VERSION 5.7 ;
BUSBITCHARS "[]" ;
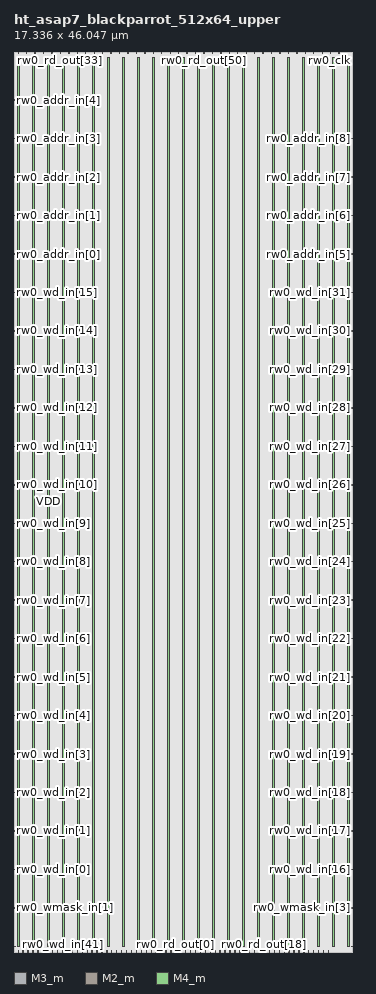
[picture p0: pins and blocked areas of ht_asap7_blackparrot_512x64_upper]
MACRO ht_asap7_blackparrot_512x64_upper
  FOREIGN ht_asap7_blackparrot_512x64_upper 0 0 ;
  SYMMETRY X Y R90 ;
  SIZE 17.336 BY 46.047 ;
  CLASS BLOCK ;
  PIN rw0_wmask_in[0]
    DIRECTION INPUT ;
    USE SIGNAL ;
    SHAPE ABUTMENT ;
    PORT
      LAYER M3_m ;
      RECT 0.000 0.276 0.072 0.300 ;
    END
  END rw0_wmask_in[0]
  PIN rw0_wmask_in[1]
    DIRECTION INPUT ;
    USE SIGNAL ;
    SHAPE ABUTMENT ;
    PORT
      LAYER M3_m ;
      RECT 0.000 2.244 0.072 2.268 ;
    END
  END rw0_wmask_in[1]
  PIN rw0_wmask_in[2]
    DIRECTION INPUT ;
    USE SIGNAL ;
    SHAPE ABUTMENT ;
    PORT
      LAYER M3_m ;
      RECT 17.264 0.276 17.336 0.300 ;
    END
  END rw0_wmask_in[2]
  PIN rw0_wmask_in[3]
    DIRECTION INPUT ;
    USE SIGNAL ;
    SHAPE ABUTMENT ;
    PORT
      LAYER M3_m ;
      RECT 17.264 2.244 17.336 2.268 ;
    END
  END rw0_wmask_in[3]
  PIN rw0_wmask_in[4]
    DIRECTION INPUT ;
    USE SIGNAL ;
    SHAPE ABUTMENT ;
    PORT
      LAYER M2_m ;
      RECT 0.207 45.993 0.225 46.047 ;
    END
  END rw0_wmask_in[4]
  PIN rw0_wmask_in[5]
    DIRECTION INPUT ;
    USE SIGNAL ;
    SHAPE ABUTMENT ;
    PORT
      LAYER M2_m ;
      RECT 0.639 45.993 0.657 46.047 ;
    END
  END rw0_wmask_in[5]
  PIN rw0_wmask_in[6]
    DIRECTION INPUT ;
    USE SIGNAL ;
    SHAPE ABUTMENT ;
    PORT
      LAYER M2_m ;
      RECT 1.071 45.993 1.089 46.047 ;
    END
  END rw0_wmask_in[6]
  PIN rw0_wmask_in[7]
    DIRECTION INPUT ;
    USE SIGNAL ;
    SHAPE ABUTMENT ;
    PORT
      LAYER M2_m ;
      RECT 1.503 45.993 1.521 46.047 ;
    END
  END rw0_wmask_in[7]
  PIN rw0_wd_in[0]
    DIRECTION INPUT ;
    USE SIGNAL ;
    SHAPE ABUTMENT ;
    PORT
      LAYER M3_m ;
      RECT 0.000 4.212 0.072 4.236 ;
    END
  END rw0_wd_in[0]
  PIN rw0_wd_in[1]
    DIRECTION INPUT ;
    USE SIGNAL ;
    SHAPE ABUTMENT ;
    PORT
      LAYER M3_m ;
      RECT 0.000 6.180 0.072 6.204 ;
    END
  END rw0_wd_in[1]
  PIN rw0_wd_in[2]
    DIRECTION INPUT ;
    USE SIGNAL ;
    SHAPE ABUTMENT ;
    PORT
      LAYER M3_m ;
      RECT 0.000 8.148 0.072 8.172 ;
    END
  END rw0_wd_in[2]
  PIN rw0_wd_in[3]
    DIRECTION INPUT ;
    USE SIGNAL ;
    SHAPE ABUTMENT ;
    PORT
      LAYER M3_m ;
      RECT 0.000 10.116 0.072 10.140 ;
    END
  END rw0_wd_in[3]
  PIN rw0_wd_in[4]
    DIRECTION INPUT ;
    USE SIGNAL ;
    SHAPE ABUTMENT ;
    PORT
      LAYER M3_m ;
      RECT 0.000 12.084 0.072 12.108 ;
    END
  END rw0_wd_in[4]
  PIN rw0_wd_in[5]
    DIRECTION INPUT ;
    USE SIGNAL ;
    SHAPE ABUTMENT ;
    PORT
      LAYER M3_m ;
      RECT 0.000 14.052 0.072 14.076 ;
    END
  END rw0_wd_in[5]
  PIN rw0_wd_in[6]
    DIRECTION INPUT ;
    USE SIGNAL ;
    SHAPE ABUTMENT ;
    PORT
      LAYER M3_m ;
      RECT 0.000 16.020 0.072 16.044 ;
    END
  END rw0_wd_in[6]
  PIN rw0_wd_in[7]
    DIRECTION INPUT ;
    USE SIGNAL ;
    SHAPE ABUTMENT ;
    PORT
      LAYER M3_m ;
      RECT 0.000 17.988 0.072 18.012 ;
    END
  END rw0_wd_in[7]
  PIN rw0_wd_in[8]
    DIRECTION INPUT ;
    USE SIGNAL ;
    SHAPE ABUTMENT ;
    PORT
      LAYER M3_m ;
      RECT 0.000 19.956 0.072 19.980 ;
    END
  END rw0_wd_in[8]
  PIN rw0_wd_in[9]
    DIRECTION INPUT ;
    USE SIGNAL ;
    SHAPE ABUTMENT ;
    PORT
      LAYER M3_m ;
      RECT 0.000 21.924 0.072 21.948 ;
    END
  END rw0_wd_in[9]
  PIN rw0_wd_in[10]
    DIRECTION INPUT ;
    USE SIGNAL ;
    SHAPE ABUTMENT ;
    PORT
      LAYER M3_m ;
      RECT 0.000 23.892 0.072 23.916 ;
    END
  END rw0_wd_in[10]
  PIN rw0_wd_in[11]
    DIRECTION INPUT ;
    USE SIGNAL ;
    SHAPE ABUTMENT ;
    PORT
      LAYER M3_m ;
      RECT 0.000 25.860 0.072 25.884 ;
    END
  END rw0_wd_in[11]
  PIN rw0_wd_in[12]
    DIRECTION INPUT ;
    USE SIGNAL ;
    SHAPE ABUTMENT ;
    PORT
      LAYER M3_m ;
      RECT 0.000 27.828 0.072 27.852 ;
    END
  END rw0_wd_in[12]
  PIN rw0_wd_in[13]
    DIRECTION INPUT ;
    USE SIGNAL ;
    SHAPE ABUTMENT ;
    PORT
      LAYER M3_m ;
      RECT 0.000 29.796 0.072 29.820 ;
    END
  END rw0_wd_in[13]
  PIN rw0_wd_in[14]
    DIRECTION INPUT ;
    USE SIGNAL ;
    SHAPE ABUTMENT ;
    PORT
      LAYER M3_m ;
      RECT 0.000 31.764 0.072 31.788 ;
    END
  END rw0_wd_in[14]
  PIN rw0_wd_in[15]
    DIRECTION INPUT ;
    USE SIGNAL ;
    SHAPE ABUTMENT ;
    PORT
      LAYER M3_m ;
      RECT 0.000 33.732 0.072 33.756 ;
    END
  END rw0_wd_in[15]
  PIN rw0_wd_in[16]
    DIRECTION INPUT ;
    USE SIGNAL ;
    SHAPE ABUTMENT ;
    PORT
      LAYER M3_m ;
      RECT 17.264 4.212 17.336 4.236 ;
    END
  END rw0_wd_in[16]
  PIN rw0_wd_in[17]
    DIRECTION INPUT ;
    USE SIGNAL ;
    SHAPE ABUTMENT ;
    PORT
      LAYER M3_m ;
      RECT 17.264 6.180 17.336 6.204 ;
    END
  END rw0_wd_in[17]
  PIN rw0_wd_in[18]
    DIRECTION INPUT ;
    USE SIGNAL ;
    SHAPE ABUTMENT ;
    PORT
      LAYER M3_m ;
      RECT 17.264 8.148 17.336 8.172 ;
    END
  END rw0_wd_in[18]
  PIN rw0_wd_in[19]
    DIRECTION INPUT ;
    USE SIGNAL ;
    SHAPE ABUTMENT ;
    PORT
      LAYER M3_m ;
      RECT 17.264 10.116 17.336 10.140 ;
    END
  END rw0_wd_in[19]
  PIN rw0_wd_in[20]
    DIRECTION INPUT ;
    USE SIGNAL ;
    SHAPE ABUTMENT ;
    PORT
      LAYER M3_m ;
      RECT 17.264 12.084 17.336 12.108 ;
    END
  END rw0_wd_in[20]
  PIN rw0_wd_in[21]
    DIRECTION INPUT ;
    USE SIGNAL ;
    SHAPE ABUTMENT ;
    PORT
      LAYER M3_m ;
      RECT 17.264 14.052 17.336 14.076 ;
    END
  END rw0_wd_in[21]
  PIN rw0_wd_in[22]
    DIRECTION INPUT ;
    USE SIGNAL ;
    SHAPE ABUTMENT ;
    PORT
      LAYER M3_m ;
      RECT 17.264 16.020 17.336 16.044 ;
    END
  END rw0_wd_in[22]
  PIN rw0_wd_in[23]
    DIRECTION INPUT ;
    USE SIGNAL ;
    SHAPE ABUTMENT ;
    PORT
      LAYER M3_m ;
      RECT 17.264 17.988 17.336 18.012 ;
    END
  END rw0_wd_in[23]
  PIN rw0_wd_in[24]
    DIRECTION INPUT ;
    USE SIGNAL ;
    SHAPE ABUTMENT ;
    PORT
      LAYER M3_m ;
      RECT 17.264 19.956 17.336 19.980 ;
    END
  END rw0_wd_in[24]
  PIN rw0_wd_in[25]
    DIRECTION INPUT ;
    USE SIGNAL ;
    SHAPE ABUTMENT ;
    PORT
      LAYER M3_m ;
      RECT 17.264 21.924 17.336 21.948 ;
    END
  END rw0_wd_in[25]
  PIN rw0_wd_in[26]
    DIRECTION INPUT ;
    USE SIGNAL ;
    SHAPE ABUTMENT ;
    PORT
      LAYER M3_m ;
      RECT 17.264 23.892 17.336 23.916 ;
    END
  END rw0_wd_in[26]
  PIN rw0_wd_in[27]
    DIRECTION INPUT ;
    USE SIGNAL ;
    SHAPE ABUTMENT ;
    PORT
      LAYER M3_m ;
      RECT 17.264 25.860 17.336 25.884 ;
    END
  END rw0_wd_in[27]
  PIN rw0_wd_in[28]
    DIRECTION INPUT ;
    USE SIGNAL ;
    SHAPE ABUTMENT ;
    PORT
      LAYER M3_m ;
      RECT 17.264 27.828 17.336 27.852 ;
    END
  END rw0_wd_in[28]
  PIN rw0_wd_in[29]
    DIRECTION INPUT ;
    USE SIGNAL ;
    SHAPE ABUTMENT ;
    PORT
      LAYER M3_m ;
      RECT 17.264 29.796 17.336 29.820 ;
    END
  END rw0_wd_in[29]
  PIN rw0_wd_in[30]
    DIRECTION INPUT ;
    USE SIGNAL ;
    SHAPE ABUTMENT ;
    PORT
      LAYER M3_m ;
      RECT 17.264 31.764 17.336 31.788 ;
    END
  END rw0_wd_in[30]
  PIN rw0_wd_in[31]
    DIRECTION INPUT ;
    USE SIGNAL ;
    SHAPE ABUTMENT ;
    PORT
      LAYER M3_m ;
      RECT 17.264 33.732 17.336 33.756 ;
    END
  END rw0_wd_in[31]
  PIN rw0_wd_in[32]
    DIRECTION INPUT ;
    USE SIGNAL ;
    SHAPE ABUTMENT ;
    PORT
      LAYER M2_m ;
      RECT 0.207 0.000 0.225 0.054 ;
    END
  END rw0_wd_in[32]
  PIN rw0_wd_in[33]
    DIRECTION INPUT ;
    USE SIGNAL ;
    SHAPE ABUTMENT ;
    PORT
      LAYER M2_m ;
      RECT 0.459 0.000 0.477 0.054 ;
    END
  END rw0_wd_in[33]
  PIN rw0_wd_in[34]
    DIRECTION INPUT ;
    USE SIGNAL ;
    SHAPE ABUTMENT ;
    PORT
      LAYER M2_m ;
      RECT 0.711 0.000 0.729 0.054 ;
    END
  END rw0_wd_in[34]
  PIN rw0_wd_in[35]
    DIRECTION INPUT ;
    USE SIGNAL ;
    SHAPE ABUTMENT ;
    PORT
      LAYER M2_m ;
      RECT 0.963 0.000 0.981 0.054 ;
    END
  END rw0_wd_in[35]
  PIN rw0_wd_in[36]
    DIRECTION INPUT ;
    USE SIGNAL ;
    SHAPE ABUTMENT ;
    PORT
      LAYER M2_m ;
      RECT 1.215 0.000 1.233 0.054 ;
    END
  END rw0_wd_in[36]
  PIN rw0_wd_in[37]
    DIRECTION INPUT ;
    USE SIGNAL ;
    SHAPE ABUTMENT ;
    PORT
      LAYER M2_m ;
      RECT 1.467 0.000 1.485 0.054 ;
    END
  END rw0_wd_in[37]
  PIN rw0_wd_in[38]
    DIRECTION INPUT ;
    USE SIGNAL ;
    SHAPE ABUTMENT ;
    PORT
      LAYER M2_m ;
      RECT 1.719 0.000 1.737 0.054 ;
    END
  END rw0_wd_in[38]
  PIN rw0_wd_in[39]
    DIRECTION INPUT ;
    USE SIGNAL ;
    SHAPE ABUTMENT ;
    PORT
      LAYER M2_m ;
      RECT 1.971 0.000 1.989 0.054 ;
    END
  END rw0_wd_in[39]
  PIN rw0_wd_in[40]
    DIRECTION INPUT ;
    USE SIGNAL ;
    SHAPE ABUTMENT ;
    PORT
      LAYER M2_m ;
      RECT 2.223 0.000 2.241 0.054 ;
    END
  END rw0_wd_in[40]
  PIN rw0_wd_in[41]
    DIRECTION INPUT ;
    USE SIGNAL ;
    SHAPE ABUTMENT ;
    PORT
      LAYER M2_m ;
      RECT 2.475 0.000 2.493 0.054 ;
    END
  END rw0_wd_in[41]
  PIN rw0_wd_in[42]
    DIRECTION INPUT ;
    USE SIGNAL ;
    SHAPE ABUTMENT ;
    PORT
      LAYER M2_m ;
      RECT 2.727 0.000 2.745 0.054 ;
    END
  END rw0_wd_in[42]
  PIN rw0_wd_in[43]
    DIRECTION INPUT ;
    USE SIGNAL ;
    SHAPE ABUTMENT ;
    PORT
      LAYER M2_m ;
      RECT 2.979 0.000 2.997 0.054 ;
    END
  END rw0_wd_in[43]
  PIN rw0_wd_in[44]
    DIRECTION INPUT ;
    USE SIGNAL ;
    SHAPE ABUTMENT ;
    PORT
      LAYER M2_m ;
      RECT 3.231 0.000 3.249 0.054 ;
    END
  END rw0_wd_in[44]
  PIN rw0_wd_in[45]
    DIRECTION INPUT ;
    USE SIGNAL ;
    SHAPE ABUTMENT ;
    PORT
      LAYER M2_m ;
      RECT 3.483 0.000 3.501 0.054 ;
    END
  END rw0_wd_in[45]
  PIN rw0_wd_in[46]
    DIRECTION INPUT ;
    USE SIGNAL ;
    SHAPE ABUTMENT ;
    PORT
      LAYER M2_m ;
      RECT 3.735 0.000 3.753 0.054 ;
    END
  END rw0_wd_in[46]
  PIN rw0_wd_in[47]
    DIRECTION INPUT ;
    USE SIGNAL ;
    SHAPE ABUTMENT ;
    PORT
      LAYER M2_m ;
      RECT 3.987 0.000 4.005 0.054 ;
    END
  END rw0_wd_in[47]
  PIN rw0_wd_in[48]
    DIRECTION INPUT ;
    USE SIGNAL ;
    SHAPE ABUTMENT ;
    PORT
      LAYER M2_m ;
      RECT 4.239 0.000 4.257 0.054 ;
    END
  END rw0_wd_in[48]
  PIN rw0_wd_in[49]
    DIRECTION INPUT ;
    USE SIGNAL ;
    SHAPE ABUTMENT ;
    PORT
      LAYER M2_m ;
      RECT 4.491 0.000 4.509 0.054 ;
    END
  END rw0_wd_in[49]
  PIN rw0_wd_in[50]
    DIRECTION INPUT ;
    USE SIGNAL ;
    SHAPE ABUTMENT ;
    PORT
      LAYER M2_m ;
      RECT 4.743 0.000 4.761 0.054 ;
    END
  END rw0_wd_in[50]
  PIN rw0_wd_in[51]
    DIRECTION INPUT ;
    USE SIGNAL ;
    SHAPE ABUTMENT ;
    PORT
      LAYER M2_m ;
      RECT 4.995 0.000 5.013 0.054 ;
    END
  END rw0_wd_in[51]
  PIN rw0_wd_in[52]
    DIRECTION INPUT ;
    USE SIGNAL ;
    SHAPE ABUTMENT ;
    PORT
      LAYER M2_m ;
      RECT 5.247 0.000 5.265 0.054 ;
    END
  END rw0_wd_in[52]
  PIN rw0_wd_in[53]
    DIRECTION INPUT ;
    USE SIGNAL ;
    SHAPE ABUTMENT ;
    PORT
      LAYER M2_m ;
      RECT 5.499 0.000 5.517 0.054 ;
    END
  END rw0_wd_in[53]
  PIN rw0_wd_in[54]
    DIRECTION INPUT ;
    USE SIGNAL ;
    SHAPE ABUTMENT ;
    PORT
      LAYER M2_m ;
      RECT 5.751 0.000 5.769 0.054 ;
    END
  END rw0_wd_in[54]
  PIN rw0_wd_in[55]
    DIRECTION INPUT ;
    USE SIGNAL ;
    SHAPE ABUTMENT ;
    PORT
      LAYER M2_m ;
      RECT 6.003 0.000 6.021 0.054 ;
    END
  END rw0_wd_in[55]
  PIN rw0_wd_in[56]
    DIRECTION INPUT ;
    USE SIGNAL ;
    SHAPE ABUTMENT ;
    PORT
      LAYER M2_m ;
      RECT 6.255 0.000 6.273 0.054 ;
    END
  END rw0_wd_in[56]
  PIN rw0_wd_in[57]
    DIRECTION INPUT ;
    USE SIGNAL ;
    SHAPE ABUTMENT ;
    PORT
      LAYER M2_m ;
      RECT 6.507 0.000 6.525 0.054 ;
    END
  END rw0_wd_in[57]
  PIN rw0_wd_in[58]
    DIRECTION INPUT ;
    USE SIGNAL ;
    SHAPE ABUTMENT ;
    PORT
      LAYER M2_m ;
      RECT 6.759 0.000 6.777 0.054 ;
    END
  END rw0_wd_in[58]
  PIN rw0_wd_in[59]
    DIRECTION INPUT ;
    USE SIGNAL ;
    SHAPE ABUTMENT ;
    PORT
      LAYER M2_m ;
      RECT 7.011 0.000 7.029 0.054 ;
    END
  END rw0_wd_in[59]
  PIN rw0_wd_in[60]
    DIRECTION INPUT ;
    USE SIGNAL ;
    SHAPE ABUTMENT ;
    PORT
      LAYER M2_m ;
      RECT 7.263 0.000 7.281 0.054 ;
    END
  END rw0_wd_in[60]
  PIN rw0_wd_in[61]
    DIRECTION INPUT ;
    USE SIGNAL ;
    SHAPE ABUTMENT ;
    PORT
      LAYER M2_m ;
      RECT 7.515 0.000 7.533 0.054 ;
    END
  END rw0_wd_in[61]
  PIN rw0_wd_in[62]
    DIRECTION INPUT ;
    USE SIGNAL ;
    SHAPE ABUTMENT ;
    PORT
      LAYER M2_m ;
      RECT 7.767 0.000 7.785 0.054 ;
    END
  END rw0_wd_in[62]
  PIN rw0_wd_in[63]
    DIRECTION INPUT ;
    USE SIGNAL ;
    SHAPE ABUTMENT ;
    PORT
      LAYER M2_m ;
      RECT 8.019 0.000 8.037 0.054 ;
    END
  END rw0_wd_in[63]
  PIN rw0_rd_out[0]
    DIRECTION OUTPUT ;
    USE SIGNAL ;
    SHAPE ABUTMENT ;
    PORT
      LAYER M2_m ;
      RECT 8.271 0.000 8.289 0.054 ;
    END
  END rw0_rd_out[0]
  PIN rw0_rd_out[1]
    DIRECTION OUTPUT ;
    USE SIGNAL ;
    SHAPE ABUTMENT ;
    PORT
      LAYER M2_m ;
      RECT 8.523 0.000 8.541 0.054 ;
    END
  END rw0_rd_out[1]
  PIN rw0_rd_out[2]
    DIRECTION OUTPUT ;
    USE SIGNAL ;
    SHAPE ABUTMENT ;
    PORT
      LAYER M2_m ;
      RECT 8.775 0.000 8.793 0.054 ;
    END
  END rw0_rd_out[2]
  PIN rw0_rd_out[3]
    DIRECTION OUTPUT ;
    USE SIGNAL ;
    SHAPE ABUTMENT ;
    PORT
      LAYER M2_m ;
      RECT 9.027 0.000 9.045 0.054 ;
    END
  END rw0_rd_out[3]
  PIN rw0_rd_out[4]
    DIRECTION OUTPUT ;
    USE SIGNAL ;
    SHAPE ABUTMENT ;
    PORT
      LAYER M2_m ;
      RECT 9.279 0.000 9.297 0.054 ;
    END
  END rw0_rd_out[4]
  PIN rw0_rd_out[5]
    DIRECTION OUTPUT ;
    USE SIGNAL ;
    SHAPE ABUTMENT ;
    PORT
      LAYER M2_m ;
      RECT 9.531 0.000 9.549 0.054 ;
    END
  END rw0_rd_out[5]
  PIN rw0_rd_out[6]
    DIRECTION OUTPUT ;
    USE SIGNAL ;
    SHAPE ABUTMENT ;
    PORT
      LAYER M2_m ;
      RECT 9.783 0.000 9.801 0.054 ;
    END
  END rw0_rd_out[6]
  PIN rw0_rd_out[7]
    DIRECTION OUTPUT ;
    USE SIGNAL ;
    SHAPE ABUTMENT ;
    PORT
      LAYER M2_m ;
      RECT 10.035 0.000 10.053 0.054 ;
    END
  END rw0_rd_out[7]
  PIN rw0_rd_out[8]
    DIRECTION OUTPUT ;
    USE SIGNAL ;
    SHAPE ABUTMENT ;
    PORT
      LAYER M2_m ;
      RECT 10.287 0.000 10.305 0.054 ;
    END
  END rw0_rd_out[8]
  PIN rw0_rd_out[9]
    DIRECTION OUTPUT ;
    USE SIGNAL ;
    SHAPE ABUTMENT ;
    PORT
      LAYER M2_m ;
      RECT 10.539 0.000 10.557 0.054 ;
    END
  END rw0_rd_out[9]
  PIN rw0_rd_out[10]
    DIRECTION OUTPUT ;
    USE SIGNAL ;
    SHAPE ABUTMENT ;
    PORT
      LAYER M2_m ;
      RECT 10.791 0.000 10.809 0.054 ;
    END
  END rw0_rd_out[10]
  PIN rw0_rd_out[11]
    DIRECTION OUTPUT ;
    USE SIGNAL ;
    SHAPE ABUTMENT ;
    PORT
      LAYER M2_m ;
      RECT 11.043 0.000 11.061 0.054 ;
    END
  END rw0_rd_out[11]
  PIN rw0_rd_out[12]
    DIRECTION OUTPUT ;
    USE SIGNAL ;
    SHAPE ABUTMENT ;
    PORT
      LAYER M2_m ;
      RECT 11.295 0.000 11.313 0.054 ;
    END
  END rw0_rd_out[12]
  PIN rw0_rd_out[13]
    DIRECTION OUTPUT ;
    USE SIGNAL ;
    SHAPE ABUTMENT ;
    PORT
      LAYER M2_m ;
      RECT 11.547 0.000 11.565 0.054 ;
    END
  END rw0_rd_out[13]
  PIN rw0_rd_out[14]
    DIRECTION OUTPUT ;
    USE SIGNAL ;
    SHAPE ABUTMENT ;
    PORT
      LAYER M2_m ;
      RECT 11.799 0.000 11.817 0.054 ;
    END
  END rw0_rd_out[14]
  PIN rw0_rd_out[15]
    DIRECTION OUTPUT ;
    USE SIGNAL ;
    SHAPE ABUTMENT ;
    PORT
      LAYER M2_m ;
      RECT 12.051 0.000 12.069 0.054 ;
    END
  END rw0_rd_out[15]
  PIN rw0_rd_out[16]
    DIRECTION OUTPUT ;
    USE SIGNAL ;
    SHAPE ABUTMENT ;
    PORT
      LAYER M2_m ;
      RECT 12.303 0.000 12.321 0.054 ;
    END
  END rw0_rd_out[16]
  PIN rw0_rd_out[17]
    DIRECTION OUTPUT ;
    USE SIGNAL ;
    SHAPE ABUTMENT ;
    PORT
      LAYER M2_m ;
      RECT 12.555 0.000 12.573 0.054 ;
    END
  END rw0_rd_out[17]
  PIN rw0_rd_out[18]
    DIRECTION OUTPUT ;
    USE SIGNAL ;
    SHAPE ABUTMENT ;
    PORT
      LAYER M2_m ;
      RECT 12.807 0.000 12.825 0.054 ;
    END
  END rw0_rd_out[18]
  PIN rw0_rd_out[19]
    DIRECTION OUTPUT ;
    USE SIGNAL ;
    SHAPE ABUTMENT ;
    PORT
      LAYER M2_m ;
      RECT 13.059 0.000 13.077 0.054 ;
    END
  END rw0_rd_out[19]
  PIN rw0_rd_out[20]
    DIRECTION OUTPUT ;
    USE SIGNAL ;
    SHAPE ABUTMENT ;
    PORT
      LAYER M2_m ;
      RECT 13.311 0.000 13.329 0.054 ;
    END
  END rw0_rd_out[20]
  PIN rw0_rd_out[21]
    DIRECTION OUTPUT ;
    USE SIGNAL ;
    SHAPE ABUTMENT ;
    PORT
      LAYER M2_m ;
      RECT 13.563 0.000 13.581 0.054 ;
    END
  END rw0_rd_out[21]
  PIN rw0_rd_out[22]
    DIRECTION OUTPUT ;
    USE SIGNAL ;
    SHAPE ABUTMENT ;
    PORT
      LAYER M2_m ;
      RECT 13.815 0.000 13.833 0.054 ;
    END
  END rw0_rd_out[22]
  PIN rw0_rd_out[23]
    DIRECTION OUTPUT ;
    USE SIGNAL ;
    SHAPE ABUTMENT ;
    PORT
      LAYER M2_m ;
      RECT 14.067 0.000 14.085 0.054 ;
    END
  END rw0_rd_out[23]
  PIN rw0_rd_out[24]
    DIRECTION OUTPUT ;
    USE SIGNAL ;
    SHAPE ABUTMENT ;
    PORT
      LAYER M2_m ;
      RECT 14.319 0.000 14.337 0.054 ;
    END
  END rw0_rd_out[24]
  PIN rw0_rd_out[25]
    DIRECTION OUTPUT ;
    USE SIGNAL ;
    SHAPE ABUTMENT ;
    PORT
      LAYER M2_m ;
      RECT 14.571 0.000 14.589 0.054 ;
    END
  END rw0_rd_out[25]
  PIN rw0_rd_out[26]
    DIRECTION OUTPUT ;
    USE SIGNAL ;
    SHAPE ABUTMENT ;
    PORT
      LAYER M2_m ;
      RECT 14.823 0.000 14.841 0.054 ;
    END
  END rw0_rd_out[26]
  PIN rw0_rd_out[27]
    DIRECTION OUTPUT ;
    USE SIGNAL ;
    SHAPE ABUTMENT ;
    PORT
      LAYER M2_m ;
      RECT 15.075 0.000 15.093 0.054 ;
    END
  END rw0_rd_out[27]
  PIN rw0_rd_out[28]
    DIRECTION OUTPUT ;
    USE SIGNAL ;
    SHAPE ABUTMENT ;
    PORT
      LAYER M2_m ;
      RECT 15.327 0.000 15.345 0.054 ;
    END
  END rw0_rd_out[28]
  PIN rw0_rd_out[29]
    DIRECTION OUTPUT ;
    USE SIGNAL ;
    SHAPE ABUTMENT ;
    PORT
      LAYER M2_m ;
      RECT 15.579 0.000 15.597 0.054 ;
    END
  END rw0_rd_out[29]
  PIN rw0_rd_out[30]
    DIRECTION OUTPUT ;
    USE SIGNAL ;
    SHAPE ABUTMENT ;
    PORT
      LAYER M2_m ;
      RECT 15.831 0.000 15.849 0.054 ;
    END
  END rw0_rd_out[30]
  PIN rw0_rd_out[31]
    DIRECTION OUTPUT ;
    USE SIGNAL ;
    SHAPE ABUTMENT ;
    PORT
      LAYER M2_m ;
      RECT 16.083 0.000 16.101 0.054 ;
    END
  END rw0_rd_out[31]
  PIN rw0_rd_out[32]
    DIRECTION OUTPUT ;
    USE SIGNAL ;
    SHAPE ABUTMENT ;
    PORT
      LAYER M2_m ;
      RECT 1.935 45.993 1.953 46.047 ;
    END
  END rw0_rd_out[32]
  PIN rw0_rd_out[33]
    DIRECTION OUTPUT ;
    USE SIGNAL ;
    SHAPE ABUTMENT ;
    PORT
      LAYER M2_m ;
      RECT 2.367 45.993 2.385 46.047 ;
    END
  END rw0_rd_out[33]
  PIN rw0_rd_out[34]
    DIRECTION OUTPUT ;
    USE SIGNAL ;
    SHAPE ABUTMENT ;
    PORT
      LAYER M2_m ;
      RECT 2.799 45.993 2.817 46.047 ;
    END
  END rw0_rd_out[34]
  PIN rw0_rd_out[35]
    DIRECTION OUTPUT ;
    USE SIGNAL ;
    SHAPE ABUTMENT ;
    PORT
      LAYER M2_m ;
      RECT 3.231 45.993 3.249 46.047 ;
    END
  END rw0_rd_out[35]
  PIN rw0_rd_out[36]
    DIRECTION OUTPUT ;
    USE SIGNAL ;
    SHAPE ABUTMENT ;
    PORT
      LAYER M2_m ;
      RECT 3.663 45.993 3.681 46.047 ;
    END
  END rw0_rd_out[36]
  PIN rw0_rd_out[37]
    DIRECTION OUTPUT ;
    USE SIGNAL ;
    SHAPE ABUTMENT ;
    PORT
      LAYER M2_m ;
      RECT 4.095 45.993 4.113 46.047 ;
    END
  END rw0_rd_out[37]
  PIN rw0_rd_out[38]
    DIRECTION OUTPUT ;
    USE SIGNAL ;
    SHAPE ABUTMENT ;
    PORT
      LAYER M2_m ;
      RECT 4.527 45.993 4.545 46.047 ;
    END
  END rw0_rd_out[38]
  PIN rw0_rd_out[39]
    DIRECTION OUTPUT ;
    USE SIGNAL ;
    SHAPE ABUTMENT ;
    PORT
      LAYER M2_m ;
      RECT 4.959 45.993 4.977 46.047 ;
    END
  END rw0_rd_out[39]
  PIN rw0_rd_out[40]
    DIRECTION OUTPUT ;
    USE SIGNAL ;
    SHAPE ABUTMENT ;
    PORT
      LAYER M2_m ;
      RECT 5.391 45.993 5.409 46.047 ;
    END
  END rw0_rd_out[40]
  PIN rw0_rd_out[41]
    DIRECTION OUTPUT ;
    USE SIGNAL ;
    SHAPE ABUTMENT ;
    PORT
      LAYER M2_m ;
      RECT 5.823 45.993 5.841 46.047 ;
    END
  END rw0_rd_out[41]
  PIN rw0_rd_out[42]
    DIRECTION OUTPUT ;
    USE SIGNAL ;
    SHAPE ABUTMENT ;
    PORT
      LAYER M2_m ;
      RECT 6.255 45.993 6.273 46.047 ;
    END
  END rw0_rd_out[42]
  PIN rw0_rd_out[43]
    DIRECTION OUTPUT ;
    USE SIGNAL ;
    SHAPE ABUTMENT ;
    PORT
      LAYER M2_m ;
      RECT 6.687 45.993 6.705 46.047 ;
    END
  END rw0_rd_out[43]
  PIN rw0_rd_out[44]
    DIRECTION OUTPUT ;
    USE SIGNAL ;
    SHAPE ABUTMENT ;
    PORT
      LAYER M2_m ;
      RECT 7.119 45.993 7.137 46.047 ;
    END
  END rw0_rd_out[44]
  PIN rw0_rd_out[45]
    DIRECTION OUTPUT ;
    USE SIGNAL ;
    SHAPE ABUTMENT ;
    PORT
      LAYER M2_m ;
      RECT 7.551 45.993 7.569 46.047 ;
    END
  END rw0_rd_out[45]
  PIN rw0_rd_out[46]
    DIRECTION OUTPUT ;
    USE SIGNAL ;
    SHAPE ABUTMENT ;
    PORT
      LAYER M2_m ;
      RECT 7.983 45.993 8.001 46.047 ;
    END
  END rw0_rd_out[46]
  PIN rw0_rd_out[47]
    DIRECTION OUTPUT ;
    USE SIGNAL ;
    SHAPE ABUTMENT ;
    PORT
      LAYER M2_m ;
      RECT 8.415 45.993 8.433 46.047 ;
    END
  END rw0_rd_out[47]
  PIN rw0_rd_out[48]
    DIRECTION OUTPUT ;
    USE SIGNAL ;
    SHAPE ABUTMENT ;
    PORT
      LAYER M2_m ;
      RECT 8.847 45.993 8.865 46.047 ;
    END
  END rw0_rd_out[48]
  PIN rw0_rd_out[49]
    DIRECTION OUTPUT ;
    USE SIGNAL ;
    SHAPE ABUTMENT ;
    PORT
      LAYER M2_m ;
      RECT 9.279 45.993 9.297 46.047 ;
    END
  END rw0_rd_out[49]
  PIN rw0_rd_out[50]
    DIRECTION OUTPUT ;
    USE SIGNAL ;
    SHAPE ABUTMENT ;
    PORT
      LAYER M2_m ;
      RECT 9.711 45.993 9.729 46.047 ;
    END
  END rw0_rd_out[50]
  PIN rw0_rd_out[51]
    DIRECTION OUTPUT ;
    USE SIGNAL ;
    SHAPE ABUTMENT ;
    PORT
      LAYER M2_m ;
      RECT 10.143 45.993 10.161 46.047 ;
    END
  END rw0_rd_out[51]
  PIN rw0_rd_out[52]
    DIRECTION OUTPUT ;
    USE SIGNAL ;
    SHAPE ABUTMENT ;
    PORT
      LAYER M2_m ;
      RECT 10.575 45.993 10.593 46.047 ;
    END
  END rw0_rd_out[52]
  PIN rw0_rd_out[53]
    DIRECTION OUTPUT ;
    USE SIGNAL ;
    SHAPE ABUTMENT ;
    PORT
      LAYER M2_m ;
      RECT 11.007 45.993 11.025 46.047 ;
    END
  END rw0_rd_out[53]
  PIN rw0_rd_out[54]
    DIRECTION OUTPUT ;
    USE SIGNAL ;
    SHAPE ABUTMENT ;
    PORT
      LAYER M2_m ;
      RECT 11.439 45.993 11.457 46.047 ;
    END
  END rw0_rd_out[54]
  PIN rw0_rd_out[55]
    DIRECTION OUTPUT ;
    USE SIGNAL ;
    SHAPE ABUTMENT ;
    PORT
      LAYER M2_m ;
      RECT 11.871 45.993 11.889 46.047 ;
    END
  END rw0_rd_out[55]
  PIN rw0_rd_out[56]
    DIRECTION OUTPUT ;
    USE SIGNAL ;
    SHAPE ABUTMENT ;
    PORT
      LAYER M2_m ;
      RECT 12.303 45.993 12.321 46.047 ;
    END
  END rw0_rd_out[56]
  PIN rw0_rd_out[57]
    DIRECTION OUTPUT ;
    USE SIGNAL ;
    SHAPE ABUTMENT ;
    PORT
      LAYER M2_m ;
      RECT 12.735 45.993 12.753 46.047 ;
    END
  END rw0_rd_out[57]
  PIN rw0_rd_out[58]
    DIRECTION OUTPUT ;
    USE SIGNAL ;
    SHAPE ABUTMENT ;
    PORT
      LAYER M2_m ;
      RECT 13.167 45.993 13.185 46.047 ;
    END
  END rw0_rd_out[58]
  PIN rw0_rd_out[59]
    DIRECTION OUTPUT ;
    USE SIGNAL ;
    SHAPE ABUTMENT ;
    PORT
      LAYER M2_m ;
      RECT 13.599 45.993 13.617 46.047 ;
    END
  END rw0_rd_out[59]
  PIN rw0_rd_out[60]
    DIRECTION OUTPUT ;
    USE SIGNAL ;
    SHAPE ABUTMENT ;
    PORT
      LAYER M2_m ;
      RECT 14.031 45.993 14.049 46.047 ;
    END
  END rw0_rd_out[60]
  PIN rw0_rd_out[61]
    DIRECTION OUTPUT ;
    USE SIGNAL ;
    SHAPE ABUTMENT ;
    PORT
      LAYER M2_m ;
      RECT 14.463 45.993 14.481 46.047 ;
    END
  END rw0_rd_out[61]
  PIN rw0_rd_out[62]
    DIRECTION OUTPUT ;
    USE SIGNAL ;
    SHAPE ABUTMENT ;
    PORT
      LAYER M2_m ;
      RECT 14.895 45.993 14.913 46.047 ;
    END
  END rw0_rd_out[62]
  PIN rw0_rd_out[63]
    DIRECTION OUTPUT ;
    USE SIGNAL ;
    SHAPE ABUTMENT ;
    PORT
      LAYER M2_m ;
      RECT 15.327 45.993 15.345 46.047 ;
    END
  END rw0_rd_out[63]
  PIN rw0_addr_in[0]
    DIRECTION INPUT ;
    USE SIGNAL ;
    SHAPE ABUTMENT ;
    PORT
      LAYER M3_m ;
      RECT 0.000 35.700 0.072 35.724 ;
    END
  END rw0_addr_in[0]
  PIN rw0_addr_in[1]
    DIRECTION INPUT ;
    USE SIGNAL ;
    SHAPE ABUTMENT ;
    PORT
      LAYER M3_m ;
      RECT 0.000 37.668 0.072 37.692 ;
    END
  END rw0_addr_in[1]
  PIN rw0_addr_in[2]
    DIRECTION INPUT ;
    USE SIGNAL ;
    SHAPE ABUTMENT ;
    PORT
      LAYER M3_m ;
      RECT 0.000 39.636 0.072 39.660 ;
    END
  END rw0_addr_in[2]
  PIN rw0_addr_in[3]
    DIRECTION INPUT ;
    USE SIGNAL ;
    SHAPE ABUTMENT ;
    PORT
      LAYER M3_m ;
      RECT 0.000 41.604 0.072 41.628 ;
    END
  END rw0_addr_in[3]
  PIN rw0_addr_in[4]
    DIRECTION INPUT ;
    USE SIGNAL ;
    SHAPE ABUTMENT ;
    PORT
      LAYER M3_m ;
      RECT 0.000 43.572 0.072 43.596 ;
    END
  END rw0_addr_in[4]
  PIN rw0_addr_in[5]
    DIRECTION INPUT ;
    USE SIGNAL ;
    SHAPE ABUTMENT ;
    PORT
      LAYER M3_m ;
      RECT 17.264 35.700 17.336 35.724 ;
    END
  END rw0_addr_in[5]
  PIN rw0_addr_in[6]
    DIRECTION INPUT ;
    USE SIGNAL ;
    SHAPE ABUTMENT ;
    PORT
      LAYER M3_m ;
      RECT 17.264 37.668 17.336 37.692 ;
    END
  END rw0_addr_in[6]
  PIN rw0_addr_in[7]
    DIRECTION INPUT ;
    USE SIGNAL ;
    SHAPE ABUTMENT ;
    PORT
      LAYER M3_m ;
      RECT 17.264 39.636 17.336 39.660 ;
    END
  END rw0_addr_in[7]
  PIN rw0_addr_in[8]
    DIRECTION INPUT ;
    USE SIGNAL ;
    SHAPE ABUTMENT ;
    PORT
      LAYER M3_m ;
      RECT 17.264 41.604 17.336 41.628 ;
    END
  END rw0_addr_in[8]
  PIN rw0_we_in
    DIRECTION INPUT ;
    USE SIGNAL ;
    SHAPE ABUTMENT ;
    PORT
      LAYER M2_m ;
      RECT 15.759 45.993 15.777 46.047 ;
    END
  END rw0_we_in
  PIN rw0_ce_in
    DIRECTION INPUT ;
    USE SIGNAL ;
    SHAPE ABUTMENT ;
    PORT
      LAYER M2_m ;
      RECT 16.191 45.993 16.209 46.047 ;
    END
  END rw0_ce_in
  PIN rw0_clk
    DIRECTION INPUT ;
    USE SIGNAL ;
    SHAPE ABUTMENT ;
    PORT
      LAYER M2_m ;
      RECT 16.623 45.993 16.641 46.047 ;
    END
  END rw0_clk
  PIN VSS
    DIRECTION INOUT ;
    USE GROUND ;
    PORT
      LAYER M4_m ;
      RECT 0.168 0.288 0.264 45.759 ;
      RECT 0.936 0.288 1.032 45.759 ;
      RECT 1.704 0.288 1.800 45.759 ;
      RECT 2.472 0.288 2.568 45.759 ;
      RECT 3.240 0.288 3.336 45.759 ;
      RECT 4.008 0.288 4.104 45.759 ;
      RECT 4.776 0.288 4.872 45.759 ;
      RECT 5.544 0.288 5.640 45.759 ;
      RECT 6.312 0.288 6.408 45.759 ;
      RECT 7.080 0.288 7.176 45.759 ;
      RECT 7.848 0.288 7.944 45.759 ;
      RECT 8.616 0.288 8.712 45.759 ;
      RECT 9.384 0.288 9.480 45.759 ;
      RECT 10.152 0.288 10.248 45.759 ;
      RECT 10.920 0.288 11.016 45.759 ;
      RECT 11.688 0.288 11.784 45.759 ;
      RECT 12.456 0.288 12.552 45.759 ;
      RECT 13.224 0.288 13.320 45.759 ;
      RECT 13.992 0.288 14.088 45.759 ;
      RECT 14.760 0.288 14.856 45.759 ;
      RECT 15.528 0.288 15.624 45.759 ;
      RECT 16.296 0.288 16.392 45.759 ;
      RECT 17.064 0.288 17.160 45.759 ;
    END
  END VSS
  PIN VDD
    DIRECTION INOUT ;
    USE POWER ;
    PORT
      LAYER M4_m ;
      RECT 0.168 0.288 0.264 45.759 ;
      RECT 0.936 0.288 1.032 45.759 ;
      RECT 1.704 0.288 1.800 45.759 ;
      RECT 2.472 0.288 2.568 45.759 ;
      RECT 3.240 0.288 3.336 45.759 ;
      RECT 4.008 0.288 4.104 45.759 ;
      RECT 4.776 0.288 4.872 45.759 ;
      RECT 5.544 0.288 5.640 45.759 ;
      RECT 6.312 0.288 6.408 45.759 ;
      RECT 7.080 0.288 7.176 45.759 ;
      RECT 7.848 0.288 7.944 45.759 ;
      RECT 8.616 0.288 8.712 45.759 ;
      RECT 9.384 0.288 9.480 45.759 ;
      RECT 10.152 0.288 10.248 45.759 ;
      RECT 10.920 0.288 11.016 45.759 ;
      RECT 11.688 0.288 11.784 45.759 ;
      RECT 12.456 0.288 12.552 45.759 ;
      RECT 13.224 0.288 13.320 45.759 ;
      RECT 13.992 0.288 14.088 45.759 ;
      RECT 14.760 0.288 14.856 45.759 ;
      RECT 15.528 0.288 15.624 45.759 ;
      RECT 16.296 0.288 16.392 45.759 ;
      RECT 17.064 0.288 17.160 45.759 ;
    END
  END VDD
  OBS
    LAYER M1_m ;
    RECT 0 0 17.336 46.047 ;
    LAYER M2_m ;
    RECT 0 0 17.336 46.047 ;
    LAYER M3_m ;
    RECT 0 0 17.336 46.047 ;
    LAYER M4_m ;
    RECT 0 0 17.336 46.047 ;
  END
END ht_asap7_blackparrot_512x64_upper

END LIBRARY
